VERSION 5.8 ;
BUSBITCHARS "[]" ;
DIVIDERCHAR "/" ;
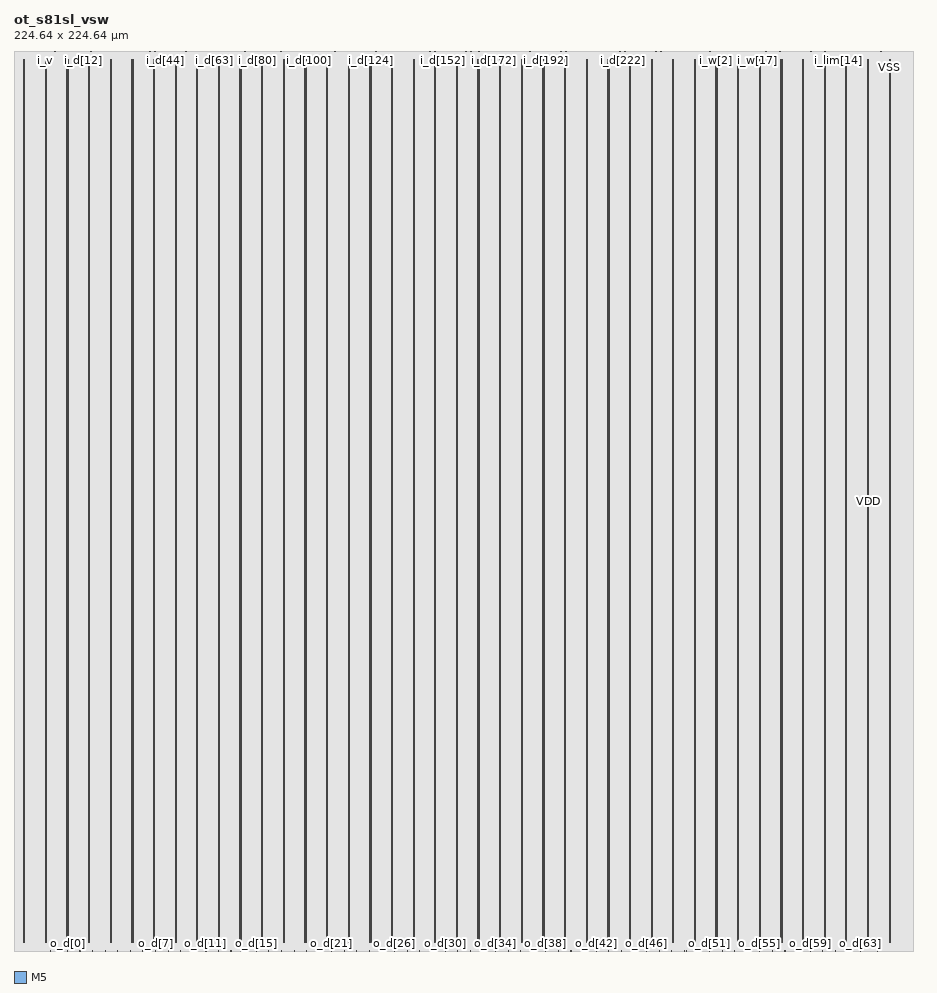
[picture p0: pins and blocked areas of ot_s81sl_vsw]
MACRO ot_s81sl_vsw
  CLASS BLOCK ;
  ORIGIN 0 0 ;
  SIZE 224.640 BY 224.640 ;
  PIN clk
    DIRECTION INPUT ;
    USE SIGNAL ;
    PORT
      LAYER M5 ;
        RECT 56.628000 0.000000 56.676000 0.480000 ;
    END
  END clk
  PIN i_d[0]
    DIRECTION INPUT ;
    USE SIGNAL ;
    PORT
      LAYER M5 ;
        RECT 9.552000 224.556000 9.576000 224.640000 ;
    END
  END i_d[0]
  PIN i_d[100]
    DIRECTION INPUT ;
    USE SIGNAL ;
    PORT
      LAYER M5 ;
        RECT 73.680000 224.556000 73.704000 224.640000 ;
    END
  END i_d[100]
  PIN i_d[101]
    DIRECTION INPUT ;
    USE SIGNAL ;
    PORT
      LAYER M5 ;
        RECT 74.304000 224.556000 74.328000 224.640000 ;
    END
  END i_d[101]
  PIN i_d[102]
    DIRECTION INPUT ;
    USE SIGNAL ;
    PORT
      LAYER M5 ;
        RECT 74.928000 224.556000 74.952000 224.640000 ;
    END
  END i_d[102]
  PIN i_d[103]
    DIRECTION INPUT ;
    USE SIGNAL ;
    PORT
      LAYER M5 ;
        RECT 75.600000 224.556000 75.624000 224.640000 ;
    END
  END i_d[103]
  PIN i_d[104]
    DIRECTION INPUT ;
    USE SIGNAL ;
    PORT
      LAYER M5 ;
        RECT 76.224000 224.556000 76.248000 224.640000 ;
    END
  END i_d[104]
  PIN i_d[105]
    DIRECTION INPUT ;
    USE SIGNAL ;
    PORT
      LAYER M5 ;
        RECT 76.896000 224.556000 76.920000 224.640000 ;
    END
  END i_d[105]
  PIN i_d[106]
    DIRECTION INPUT ;
    USE SIGNAL ;
    PORT
      LAYER M5 ;
        RECT 77.520000 224.556000 77.544000 224.640000 ;
    END
  END i_d[106]
  PIN i_d[107]
    DIRECTION INPUT ;
    USE SIGNAL ;
    PORT
      LAYER M5 ;
        RECT 78.144000 224.556000 78.168000 224.640000 ;
    END
  END i_d[107]
  PIN i_d[108]
    DIRECTION INPUT ;
    USE SIGNAL ;
    PORT
      LAYER M5 ;
        RECT 78.816000 224.556000 78.840000 224.640000 ;
    END
  END i_d[108]
  PIN i_d[109]
    DIRECTION INPUT ;
    USE SIGNAL ;
    PORT
      LAYER M5 ;
        RECT 79.440000 224.556000 79.464000 224.640000 ;
    END
  END i_d[109]
  PIN i_d[10]
    DIRECTION INPUT ;
    USE SIGNAL ;
    PORT
      LAYER M5 ;
        RECT 15.984000 224.556000 16.008000 224.640000 ;
    END
  END i_d[10]
  PIN i_d[110]
    DIRECTION INPUT ;
    USE SIGNAL ;
    PORT
      LAYER M5 ;
        RECT 80.112000 224.556000 80.136000 224.640000 ;
    END
  END i_d[110]
  PIN i_d[111]
    DIRECTION INPUT ;
    USE SIGNAL ;
    PORT
      LAYER M5 ;
        RECT 80.736000 224.556000 80.760000 224.640000 ;
    END
  END i_d[111]
  PIN i_d[112]
    DIRECTION INPUT ;
    USE SIGNAL ;
    PORT
      LAYER M5 ;
        RECT 81.408000 224.556000 81.432000 224.640000 ;
    END
  END i_d[112]
  PIN i_d[113]
    DIRECTION INPUT ;
    USE SIGNAL ;
    PORT
      LAYER M5 ;
        RECT 82.032000 224.556000 82.056000 224.640000 ;
    END
  END i_d[113]
  PIN i_d[114]
    DIRECTION INPUT ;
    USE SIGNAL ;
    PORT
      LAYER M5 ;
        RECT 82.656000 224.556000 82.680000 224.640000 ;
    END
  END i_d[114]
  PIN i_d[115]
    DIRECTION INPUT ;
    USE SIGNAL ;
    PORT
      LAYER M5 ;
        RECT 83.280000 224.556000 83.304000 224.640000 ;
    END
  END i_d[115]
  PIN i_d[116]
    DIRECTION INPUT ;
    USE SIGNAL ;
    PORT
      LAYER M5 ;
        RECT 83.952000 224.556000 83.976000 224.640000 ;
    END
  END i_d[116]
  PIN i_d[117]
    DIRECTION INPUT ;
    USE SIGNAL ;
    PORT
      LAYER M5 ;
        RECT 84.576000 224.556000 84.600000 224.640000 ;
    END
  END i_d[117]
  PIN i_d[118]
    DIRECTION INPUT ;
    USE SIGNAL ;
    PORT
      LAYER M5 ;
        RECT 85.200000 224.556000 85.224000 224.640000 ;
    END
  END i_d[118]
  PIN i_d[119]
    DIRECTION INPUT ;
    USE SIGNAL ;
    PORT
      LAYER M5 ;
        RECT 85.872000 224.556000 85.896000 224.640000 ;
    END
  END i_d[119]
  PIN i_d[11]
    DIRECTION INPUT ;
    USE SIGNAL ;
    PORT
      LAYER M5 ;
        RECT 16.656000 224.556000 16.680000 224.640000 ;
    END
  END i_d[11]
  PIN i_d[120]
    DIRECTION INPUT ;
    USE SIGNAL ;
    PORT
      LAYER M5 ;
        RECT 86.496000 224.556000 86.520000 224.640000 ;
    END
  END i_d[120]
  PIN i_d[121]
    DIRECTION INPUT ;
    USE SIGNAL ;
    PORT
      LAYER M5 ;
        RECT 87.120000 224.556000 87.144000 224.640000 ;
    END
  END i_d[121]
  PIN i_d[122]
    DIRECTION INPUT ;
    USE SIGNAL ;
    PORT
      LAYER M5 ;
        RECT 87.744000 224.556000 87.768000 224.640000 ;
    END
  END i_d[122]
  PIN i_d[123]
    DIRECTION INPUT ;
    USE SIGNAL ;
    PORT
      LAYER M5 ;
        RECT 88.416000 224.556000 88.440000 224.640000 ;
    END
  END i_d[123]
  PIN i_d[124]
    DIRECTION INPUT ;
    USE SIGNAL ;
    PORT
      LAYER M5 ;
        RECT 89.040000 224.556000 89.064000 224.640000 ;
    END
  END i_d[124]
  PIN i_d[125]
    DIRECTION INPUT ;
    USE SIGNAL ;
    PORT
      LAYER M5 ;
        RECT 89.712000 224.556000 89.736000 224.640000 ;
    END
  END i_d[125]
  PIN i_d[126]
    DIRECTION INPUT ;
    USE SIGNAL ;
    PORT
      LAYER M5 ;
        RECT 90.336000 224.556000 90.360000 224.640000 ;
    END
  END i_d[126]
  PIN i_d[127]
    DIRECTION INPUT ;
    USE SIGNAL ;
    PORT
      LAYER M5 ;
        RECT 91.008000 224.556000 91.032000 224.640000 ;
    END
  END i_d[127]
  PIN i_d[128]
    DIRECTION INPUT ;
    USE SIGNAL ;
    PORT
      LAYER M5 ;
        RECT 91.632000 224.556000 91.656000 224.640000 ;
    END
  END i_d[128]
  PIN i_d[129]
    DIRECTION INPUT ;
    USE SIGNAL ;
    PORT
      LAYER M5 ;
        RECT 92.256000 224.556000 92.280000 224.640000 ;
    END
  END i_d[129]
  PIN i_d[12]
    DIRECTION INPUT ;
    USE SIGNAL ;
    PORT
      LAYER M5 ;
        RECT 17.280000 224.556000 17.304000 224.640000 ;
    END
  END i_d[12]
  PIN i_d[130]
    DIRECTION INPUT ;
    USE SIGNAL ;
    PORT
      LAYER M5 ;
        RECT 92.928000 224.556000 92.952000 224.640000 ;
    END
  END i_d[130]
  PIN i_d[131]
    DIRECTION INPUT ;
    USE SIGNAL ;
    PORT
      LAYER M5 ;
        RECT 93.552000 224.556000 93.576000 224.640000 ;
    END
  END i_d[131]
  PIN i_d[132]
    DIRECTION INPUT ;
    USE SIGNAL ;
    PORT
      LAYER M5 ;
        RECT 94.176000 224.556000 94.200000 224.640000 ;
    END
  END i_d[132]
  PIN i_d[133]
    DIRECTION INPUT ;
    USE SIGNAL ;
    PORT
      LAYER M5 ;
        RECT 94.848000 224.556000 94.872000 224.640000 ;
    END
  END i_d[133]
  PIN i_d[134]
    DIRECTION INPUT ;
    USE SIGNAL ;
    PORT
      LAYER M5 ;
        RECT 95.472000 224.556000 95.496000 224.640000 ;
    END
  END i_d[134]
  PIN i_d[135]
    DIRECTION INPUT ;
    USE SIGNAL ;
    PORT
      LAYER M5 ;
        RECT 96.096000 224.556000 96.120000 224.640000 ;
    END
  END i_d[135]
  PIN i_d[136]
    DIRECTION INPUT ;
    USE SIGNAL ;
    PORT
      LAYER M5 ;
        RECT 96.768000 224.556000 96.792000 224.640000 ;
    END
  END i_d[136]
  PIN i_d[137]
    DIRECTION INPUT ;
    USE SIGNAL ;
    PORT
      LAYER M5 ;
        RECT 97.392000 224.556000 97.416000 224.640000 ;
    END
  END i_d[137]
  PIN i_d[138]
    DIRECTION INPUT ;
    USE SIGNAL ;
    PORT
      LAYER M5 ;
        RECT 98.016000 224.556000 98.040000 224.640000 ;
    END
  END i_d[138]
  PIN i_d[139]
    DIRECTION INPUT ;
    USE SIGNAL ;
    PORT
      LAYER M5 ;
        RECT 98.688000 224.556000 98.712000 224.640000 ;
    END
  END i_d[139]
  PIN i_d[13]
    DIRECTION INPUT ;
    USE SIGNAL ;
    PORT
      LAYER M5 ;
        RECT 17.904000 224.556000 17.928000 224.640000 ;
    END
  END i_d[13]
  PIN i_d[140]
    DIRECTION INPUT ;
    USE SIGNAL ;
    PORT
      LAYER M5 ;
        RECT 99.312000 224.556000 99.336000 224.640000 ;
    END
  END i_d[140]
  PIN i_d[141]
    DIRECTION INPUT ;
    USE SIGNAL ;
    PORT
      LAYER M5 ;
        RECT 99.936000 224.556000 99.960000 224.640000 ;
    END
  END i_d[141]
  PIN i_d[142]
    DIRECTION INPUT ;
    USE SIGNAL ;
    PORT
      LAYER M5 ;
        RECT 100.560000 224.556000 100.584000 224.640000 ;
    END
  END i_d[142]
  PIN i_d[143]
    DIRECTION INPUT ;
    USE SIGNAL ;
    PORT
      LAYER M5 ;
        RECT 101.232000 224.556000 101.256000 224.640000 ;
    END
  END i_d[143]
  PIN i_d[144]
    DIRECTION INPUT ;
    USE SIGNAL ;
    PORT
      LAYER M5 ;
        RECT 101.856000 224.556000 101.880000 224.640000 ;
    END
  END i_d[144]
  PIN i_d[145]
    DIRECTION INPUT ;
    USE SIGNAL ;
    PORT
      LAYER M5 ;
        RECT 102.528000 224.556000 102.552000 224.640000 ;
    END
  END i_d[145]
  PIN i_d[146]
    DIRECTION INPUT ;
    USE SIGNAL ;
    PORT
      LAYER M5 ;
        RECT 103.152000 224.556000 103.176000 224.640000 ;
    END
  END i_d[146]
  PIN i_d[147]
    DIRECTION INPUT ;
    USE SIGNAL ;
    PORT
      LAYER M5 ;
        RECT 103.824000 224.556000 103.848000 224.640000 ;
    END
  END i_d[147]
  PIN i_d[148]
    DIRECTION INPUT ;
    USE SIGNAL ;
    PORT
      LAYER M5 ;
        RECT 104.448000 224.556000 104.472000 224.640000 ;
    END
  END i_d[148]
  PIN i_d[149]
    DIRECTION INPUT ;
    USE SIGNAL ;
    PORT
      LAYER M5 ;
        RECT 105.072000 224.556000 105.096000 224.640000 ;
    END
  END i_d[149]
  PIN i_d[14]
    DIRECTION INPUT ;
    USE SIGNAL ;
    PORT
      LAYER M5 ;
        RECT 18.576000 224.556000 18.600000 224.640000 ;
    END
  END i_d[14]
  PIN i_d[150]
    DIRECTION INPUT ;
    USE SIGNAL ;
    PORT
      LAYER M5 ;
        RECT 105.744000 224.556000 105.768000 224.640000 ;
    END
  END i_d[150]
  PIN i_d[151]
    DIRECTION INPUT ;
    USE SIGNAL ;
    PORT
      LAYER M5 ;
        RECT 106.368000 224.556000 106.392000 224.640000 ;
    END
  END i_d[151]
  PIN i_d[152]
    DIRECTION INPUT ;
    USE SIGNAL ;
    PORT
      LAYER M5 ;
        RECT 107.040000 224.556000 107.064000 224.640000 ;
    END
  END i_d[152]
  PIN i_d[153]
    DIRECTION INPUT ;
    USE SIGNAL ;
    PORT
      LAYER M5 ;
        RECT 107.664000 224.556000 107.688000 224.640000 ;
    END
  END i_d[153]
  PIN i_d[154]
    DIRECTION INPUT ;
    USE SIGNAL ;
    PORT
      LAYER M5 ;
        RECT 108.288000 224.556000 108.312000 224.640000 ;
    END
  END i_d[154]
  PIN i_d[155]
    DIRECTION INPUT ;
    USE SIGNAL ;
    PORT
      LAYER M5 ;
        RECT 108.912000 224.556000 108.936000 224.640000 ;
    END
  END i_d[155]
  PIN i_d[156]
    DIRECTION INPUT ;
    USE SIGNAL ;
    PORT
      LAYER M5 ;
        RECT 109.584000 224.556000 109.608000 224.640000 ;
    END
  END i_d[156]
  PIN i_d[157]
    DIRECTION INPUT ;
    USE SIGNAL ;
    PORT
      LAYER M5 ;
        RECT 110.208000 224.556000 110.232000 224.640000 ;
    END
  END i_d[157]
  PIN i_d[158]
    DIRECTION INPUT ;
    USE SIGNAL ;
    PORT
      LAYER M5 ;
        RECT 110.832000 224.556000 110.856000 224.640000 ;
    END
  END i_d[158]
  PIN i_d[159]
    DIRECTION INPUT ;
    USE SIGNAL ;
    PORT
      LAYER M5 ;
        RECT 111.504000 224.556000 111.528000 224.640000 ;
    END
  END i_d[159]
  PIN i_d[15]
    DIRECTION INPUT ;
    USE SIGNAL ;
    PORT
      LAYER M5 ;
        RECT 19.200000 224.556000 19.224000 224.640000 ;
    END
  END i_d[15]
  PIN i_d[160]
    DIRECTION INPUT ;
    USE SIGNAL ;
    PORT
      LAYER M5 ;
        RECT 112.128000 224.556000 112.152000 224.640000 ;
    END
  END i_d[160]
  PIN i_d[161]
    DIRECTION INPUT ;
    USE SIGNAL ;
    PORT
      LAYER M5 ;
        RECT 112.800000 224.556000 112.824000 224.640000 ;
    END
  END i_d[161]
  PIN i_d[162]
    DIRECTION INPUT ;
    USE SIGNAL ;
    PORT
      LAYER M5 ;
        RECT 113.424000 224.556000 113.448000 224.640000 ;
    END
  END i_d[162]
  PIN i_d[163]
    DIRECTION INPUT ;
    USE SIGNAL ;
    PORT
      LAYER M5 ;
        RECT 114.048000 224.556000 114.072000 224.640000 ;
    END
  END i_d[163]
  PIN i_d[164]
    DIRECTION INPUT ;
    USE SIGNAL ;
    PORT
      LAYER M5 ;
        RECT 114.672000 224.556000 114.696000 224.640000 ;
    END
  END i_d[164]
  PIN i_d[165]
    DIRECTION INPUT ;
    USE SIGNAL ;
    PORT
      LAYER M5 ;
        RECT 115.344000 224.556000 115.368000 224.640000 ;
    END
  END i_d[165]
  PIN i_d[166]
    DIRECTION INPUT ;
    USE SIGNAL ;
    PORT
      LAYER M5 ;
        RECT 116.064000 224.556000 116.088000 224.640000 ;
    END
  END i_d[166]
  PIN i_d[167]
    DIRECTION INPUT ;
    USE SIGNAL ;
    PORT
      LAYER M5 ;
        RECT 116.640000 224.556000 116.664000 224.640000 ;
    END
  END i_d[167]
  PIN i_d[168]
    DIRECTION INPUT ;
    USE SIGNAL ;
    PORT
      LAYER M5 ;
        RECT 117.264000 224.556000 117.288000 224.640000 ;
    END
  END i_d[168]
  PIN i_d[169]
    DIRECTION INPUT ;
    USE SIGNAL ;
    PORT
      LAYER M5 ;
        RECT 117.888000 224.556000 117.912000 224.640000 ;
    END
  END i_d[169]
  PIN i_d[16]
    DIRECTION INPUT ;
    USE SIGNAL ;
    PORT
      LAYER M5 ;
        RECT 19.824000 224.556000 19.848000 224.640000 ;
    END
  END i_d[16]
  PIN i_d[170]
    DIRECTION INPUT ;
    USE SIGNAL ;
    PORT
      LAYER M5 ;
        RECT 118.560000 224.556000 118.584000 224.640000 ;
    END
  END i_d[170]
  PIN i_d[171]
    DIRECTION INPUT ;
    USE SIGNAL ;
    PORT
      LAYER M5 ;
        RECT 119.184000 224.556000 119.208000 224.640000 ;
    END
  END i_d[171]
  PIN i_d[172]
    DIRECTION INPUT ;
    USE SIGNAL ;
    PORT
      LAYER M5 ;
        RECT 119.856000 224.556000 119.880000 224.640000 ;
    END
  END i_d[172]
  PIN i_d[173]
    DIRECTION INPUT ;
    USE SIGNAL ;
    PORT
      LAYER M5 ;
        RECT 120.480000 224.556000 120.504000 224.640000 ;
    END
  END i_d[173]
  PIN i_d[174]
    DIRECTION INPUT ;
    USE SIGNAL ;
    PORT
      LAYER M5 ;
        RECT 121.104000 224.556000 121.128000 224.640000 ;
    END
  END i_d[174]
  PIN i_d[175]
    DIRECTION INPUT ;
    USE SIGNAL ;
    PORT
      LAYER M5 ;
        RECT 121.728000 224.556000 121.752000 224.640000 ;
    END
  END i_d[175]
  PIN i_d[176]
    DIRECTION INPUT ;
    USE SIGNAL ;
    PORT
      LAYER M5 ;
        RECT 122.400000 224.556000 122.424000 224.640000 ;
    END
  END i_d[176]
  PIN i_d[177]
    DIRECTION INPUT ;
    USE SIGNAL ;
    PORT
      LAYER M5 ;
        RECT 123.024000 224.556000 123.048000 224.640000 ;
    END
  END i_d[177]
  PIN i_d[178]
    DIRECTION INPUT ;
    USE SIGNAL ;
    PORT
      LAYER M5 ;
        RECT 123.648000 224.556000 123.672000 224.640000 ;
    END
  END i_d[178]
  PIN i_d[179]
    DIRECTION INPUT ;
    USE SIGNAL ;
    PORT
      LAYER M5 ;
        RECT 124.320000 224.556000 124.344000 224.640000 ;
    END
  END i_d[179]
  PIN i_d[17]
    DIRECTION INPUT ;
    USE SIGNAL ;
    PORT
      LAYER M5 ;
        RECT 20.496000 224.556000 20.520000 224.640000 ;
    END
  END i_d[17]
  PIN i_d[180]
    DIRECTION INPUT ;
    USE SIGNAL ;
    PORT
      LAYER M5 ;
        RECT 124.944000 224.556000 124.968000 224.640000 ;
    END
  END i_d[180]
  PIN i_d[181]
    DIRECTION INPUT ;
    USE SIGNAL ;
    PORT
      LAYER M5 ;
        RECT 125.616000 224.556000 125.640000 224.640000 ;
    END
  END i_d[181]
  PIN i_d[182]
    DIRECTION INPUT ;
    USE SIGNAL ;
    PORT
      LAYER M5 ;
        RECT 126.240000 224.556000 126.264000 224.640000 ;
    END
  END i_d[182]
  PIN i_d[183]
    DIRECTION INPUT ;
    USE SIGNAL ;
    PORT
      LAYER M5 ;
        RECT 126.864000 224.556000 126.888000 224.640000 ;
    END
  END i_d[183]
  PIN i_d[184]
    DIRECTION INPUT ;
    USE SIGNAL ;
    PORT
      LAYER M5 ;
        RECT 127.488000 224.556000 127.512000 224.640000 ;
    END
  END i_d[184]
  PIN i_d[185]
    DIRECTION INPUT ;
    USE SIGNAL ;
    PORT
      LAYER M5 ;
        RECT 128.160000 224.556000 128.184000 224.640000 ;
    END
  END i_d[185]
  PIN i_d[186]
    DIRECTION INPUT ;
    USE SIGNAL ;
    PORT
      LAYER M5 ;
        RECT 128.784000 224.556000 128.808000 224.640000 ;
    END
  END i_d[186]
  PIN i_d[187]
    DIRECTION INPUT ;
    USE SIGNAL ;
    PORT
      LAYER M5 ;
        RECT 129.456000 224.556000 129.480000 224.640000 ;
    END
  END i_d[187]
  PIN i_d[188]
    DIRECTION INPUT ;
    USE SIGNAL ;
    PORT
      LAYER M5 ;
        RECT 130.080000 224.556000 130.104000 224.640000 ;
    END
  END i_d[188]
  PIN i_d[189]
    DIRECTION INPUT ;
    USE SIGNAL ;
    PORT
      LAYER M5 ;
        RECT 130.704000 224.556000 130.728000 224.640000 ;
    END
  END i_d[189]
  PIN i_d[18]
    DIRECTION INPUT ;
    USE SIGNAL ;
    PORT
      LAYER M5 ;
        RECT 21.120000 224.556000 21.144000 224.640000 ;
    END
  END i_d[18]
  PIN i_d[190]
    DIRECTION INPUT ;
    USE SIGNAL ;
    PORT
      LAYER M5 ;
        RECT 131.376000 224.556000 131.400000 224.640000 ;
    END
  END i_d[190]
  PIN i_d[191]
    DIRECTION INPUT ;
    USE SIGNAL ;
    PORT
      LAYER M5 ;
        RECT 132.000000 224.556000 132.024000 224.640000 ;
    END
  END i_d[191]
  PIN i_d[192]
    DIRECTION INPUT ;
    USE SIGNAL ;
    PORT
      LAYER M5 ;
        RECT 132.672000 224.556000 132.696000 224.640000 ;
    END
  END i_d[192]
  PIN i_d[193]
    DIRECTION INPUT ;
    USE SIGNAL ;
    PORT
      LAYER M5 ;
        RECT 133.296000 224.556000 133.320000 224.640000 ;
    END
  END i_d[193]
  PIN i_d[194]
    DIRECTION INPUT ;
    USE SIGNAL ;
    PORT
      LAYER M5 ;
        RECT 133.920000 224.556000 133.944000 224.640000 ;
    END
  END i_d[194]
  PIN i_d[195]
    DIRECTION INPUT ;
    USE SIGNAL ;
    PORT
      LAYER M5 ;
        RECT 134.592000 224.556000 134.616000 224.640000 ;
    END
  END i_d[195]
  PIN i_d[196]
    DIRECTION INPUT ;
    USE SIGNAL ;
    PORT
      LAYER M5 ;
        RECT 135.216000 224.556000 135.240000 224.640000 ;
    END
  END i_d[196]
  PIN i_d[197]
    DIRECTION INPUT ;
    USE SIGNAL ;
    PORT
      LAYER M5 ;
        RECT 135.840000 224.556000 135.864000 224.640000 ;
    END
  END i_d[197]
  PIN i_d[198]
    DIRECTION INPUT ;
    USE SIGNAL ;
    PORT
      LAYER M5 ;
        RECT 136.512000 224.556000 136.536000 224.640000 ;
    END
  END i_d[198]
  PIN i_d[199]
    DIRECTION INPUT ;
    USE SIGNAL ;
    PORT
      LAYER M5 ;
        RECT 137.136000 224.556000 137.160000 224.640000 ;
    END
  END i_d[199]
  PIN i_d[19]
    DIRECTION INPUT ;
    USE SIGNAL ;
    PORT
      LAYER M5 ;
        RECT 21.744000 224.556000 21.768000 224.640000 ;
    END
  END i_d[19]
  PIN i_d[1]
    DIRECTION INPUT ;
    USE SIGNAL ;
    PORT
      LAYER M5 ;
        RECT 10.224000 224.556000 10.248000 224.640000 ;
    END
  END i_d[1]
  PIN i_d[200]
    DIRECTION INPUT ;
    USE SIGNAL ;
    PORT
      LAYER M5 ;
        RECT 137.760000 224.556000 137.784000 224.640000 ;
    END
  END i_d[200]
  PIN i_d[201]
    DIRECTION INPUT ;
    USE SIGNAL ;
    PORT
      LAYER M5 ;
        RECT 138.432000 224.556000 138.456000 224.640000 ;
    END
  END i_d[201]
  PIN i_d[202]
    DIRECTION INPUT ;
    USE SIGNAL ;
    PORT
      LAYER M5 ;
        RECT 139.056000 224.556000 139.080000 224.640000 ;
    END
  END i_d[202]
  PIN i_d[203]
    DIRECTION INPUT ;
    USE SIGNAL ;
    PORT
      LAYER M5 ;
        RECT 139.680000 224.556000 139.704000 224.640000 ;
    END
  END i_d[203]
  PIN i_d[204]
    DIRECTION INPUT ;
    USE SIGNAL ;
    PORT
      LAYER M5 ;
        RECT 140.304000 224.556000 140.328000 224.640000 ;
    END
  END i_d[204]
  PIN i_d[205]
    DIRECTION INPUT ;
    USE SIGNAL ;
    PORT
      LAYER M5 ;
        RECT 140.976000 224.556000 141.000000 224.640000 ;
    END
  END i_d[205]
  PIN i_d[206]
    DIRECTION INPUT ;
    USE SIGNAL ;
    PORT
      LAYER M5 ;
        RECT 141.600000 224.556000 141.624000 224.640000 ;
    END
  END i_d[206]
  PIN i_d[207]
    DIRECTION INPUT ;
    USE SIGNAL ;
    PORT
      LAYER M5 ;
        RECT 142.272000 224.556000 142.296000 224.640000 ;
    END
  END i_d[207]
  PIN i_d[208]
    DIRECTION INPUT ;
    USE SIGNAL ;
    PORT
      LAYER M5 ;
        RECT 142.896000 224.556000 142.920000 224.640000 ;
    END
  END i_d[208]
  PIN i_d[209]
    DIRECTION INPUT ;
    USE SIGNAL ;
    PORT
      LAYER M5 ;
        RECT 143.520000 224.556000 143.544000 224.640000 ;
    END
  END i_d[209]
  PIN i_d[20]
    DIRECTION INPUT ;
    USE SIGNAL ;
    PORT
      LAYER M5 ;
        RECT 22.368000 224.556000 22.392000 224.640000 ;
    END
  END i_d[20]
  PIN i_d[210]
    DIRECTION INPUT ;
    USE SIGNAL ;
    PORT
      LAYER M5 ;
        RECT 144.192000 224.556000 144.216000 224.640000 ;
    END
  END i_d[210]
  PIN i_d[211]
    DIRECTION INPUT ;
    USE SIGNAL ;
    PORT
      LAYER M5 ;
        RECT 144.816000 224.556000 144.840000 224.640000 ;
    END
  END i_d[211]
  PIN i_d[212]
    DIRECTION INPUT ;
    USE SIGNAL ;
    PORT
      LAYER M5 ;
        RECT 145.488000 224.556000 145.512000 224.640000 ;
    END
  END i_d[212]
  PIN i_d[213]
    DIRECTION INPUT ;
    USE SIGNAL ;
    PORT
      LAYER M5 ;
        RECT 146.112000 224.556000 146.136000 224.640000 ;
    END
  END i_d[213]
  PIN i_d[214]
    DIRECTION INPUT ;
    USE SIGNAL ;
    PORT
      LAYER M5 ;
        RECT 146.736000 224.556000 146.760000 224.640000 ;
    END
  END i_d[214]
  PIN i_d[215]
    DIRECTION INPUT ;
    USE SIGNAL ;
    PORT
      LAYER M5 ;
        RECT 147.408000 224.556000 147.432000 224.640000 ;
    END
  END i_d[215]
  PIN i_d[216]
    DIRECTION INPUT ;
    USE SIGNAL ;
    PORT
      LAYER M5 ;
        RECT 148.032000 224.556000 148.056000 224.640000 ;
    END
  END i_d[216]
  PIN i_d[217]
    DIRECTION INPUT ;
    USE SIGNAL ;
    PORT
      LAYER M5 ;
        RECT 148.656000 224.556000 148.680000 224.640000 ;
    END
  END i_d[217]
  PIN i_d[218]
    DIRECTION INPUT ;
    USE SIGNAL ;
    PORT
      LAYER M5 ;
        RECT 149.328000 224.556000 149.352000 224.640000 ;
    END
  END i_d[218]
  PIN i_d[219]
    DIRECTION INPUT ;
    USE SIGNAL ;
    PORT
      LAYER M5 ;
        RECT 149.952000 224.556000 149.976000 224.640000 ;
    END
  END i_d[219]
  PIN i_d[21]
    DIRECTION INPUT ;
    USE SIGNAL ;
    PORT
      LAYER M5 ;
        RECT 23.040000 224.556000 23.064000 224.640000 ;
    END
  END i_d[21]
  PIN i_d[220]
    DIRECTION INPUT ;
    USE SIGNAL ;
    PORT
      LAYER M5 ;
        RECT 150.576000 224.556000 150.600000 224.640000 ;
    END
  END i_d[220]
  PIN i_d[221]
    DIRECTION INPUT ;
    USE SIGNAL ;
    PORT
      LAYER M5 ;
        RECT 151.248000 224.556000 151.272000 224.640000 ;
    END
  END i_d[221]
  PIN i_d[222]
    DIRECTION INPUT ;
    USE SIGNAL ;
    PORT
      LAYER M5 ;
        RECT 151.872000 224.556000 151.896000 224.640000 ;
    END
  END i_d[222]
  PIN i_d[223]
    DIRECTION INPUT ;
    USE SIGNAL ;
    PORT
      LAYER M5 ;
        RECT 152.496000 224.556000 152.520000 224.640000 ;
    END
  END i_d[223]
  PIN i_d[224]
    DIRECTION INPUT ;
    USE SIGNAL ;
    PORT
      LAYER M5 ;
        RECT 153.120000 224.556000 153.144000 224.640000 ;
    END
  END i_d[224]
  PIN i_d[225]
    DIRECTION INPUT ;
    USE SIGNAL ;
    PORT
      LAYER M5 ;
        RECT 153.792000 224.556000 153.816000 224.640000 ;
    END
  END i_d[225]
  PIN i_d[226]
    DIRECTION INPUT ;
    USE SIGNAL ;
    PORT
      LAYER M5 ;
        RECT 154.416000 224.556000 154.440000 224.640000 ;
    END
  END i_d[226]
  PIN i_d[227]
    DIRECTION INPUT ;
    USE SIGNAL ;
    PORT
      LAYER M5 ;
        RECT 155.088000 224.556000 155.112000 224.640000 ;
    END
  END i_d[227]
  PIN i_d[228]
    DIRECTION INPUT ;
    USE SIGNAL ;
    PORT
      LAYER M5 ;
        RECT 155.712000 224.556000 155.736000 224.640000 ;
    END
  END i_d[228]
  PIN i_d[229]
    DIRECTION INPUT ;
    USE SIGNAL ;
    PORT
      LAYER M5 ;
        RECT 156.384000 224.556000 156.408000 224.640000 ;
    END
  END i_d[229]
  PIN i_d[22]
    DIRECTION INPUT ;
    USE SIGNAL ;
    PORT
      LAYER M5 ;
        RECT 23.664000 224.556000 23.688000 224.640000 ;
    END
  END i_d[22]
  PIN i_d[230]
    DIRECTION INPUT ;
    USE SIGNAL ;
    PORT
      LAYER M5 ;
        RECT 157.008000 224.556000 157.032000 224.640000 ;
    END
  END i_d[230]
  PIN i_d[231]
    DIRECTION INPUT ;
    USE SIGNAL ;
    PORT
      LAYER M5 ;
        RECT 157.632000 224.556000 157.656000 224.640000 ;
    END
  END i_d[231]
  PIN i_d[232]
    DIRECTION INPUT ;
    USE SIGNAL ;
    PORT
      LAYER M5 ;
        RECT 158.304000 224.556000 158.328000 224.640000 ;
    END
  END i_d[232]
  PIN i_d[233]
    DIRECTION INPUT ;
    USE SIGNAL ;
    PORT
      LAYER M5 ;
        RECT 158.928000 224.556000 158.952000 224.640000 ;
    END
  END i_d[233]
  PIN i_d[234]
    DIRECTION INPUT ;
    USE SIGNAL ;
    PORT
      LAYER M5 ;
        RECT 159.552000 224.556000 159.576000 224.640000 ;
    END
  END i_d[234]
  PIN i_d[235]
    DIRECTION INPUT ;
    USE SIGNAL ;
    PORT
      LAYER M5 ;
        RECT 160.224000 224.556000 160.248000 224.640000 ;
    END
  END i_d[235]
  PIN i_d[236]
    DIRECTION INPUT ;
    USE SIGNAL ;
    PORT
      LAYER M5 ;
        RECT 160.848000 224.556000 160.872000 224.640000 ;
    END
  END i_d[236]
  PIN i_d[237]
    DIRECTION INPUT ;
    USE SIGNAL ;
    PORT
      LAYER M5 ;
        RECT 161.472000 224.556000 161.496000 224.640000 ;
    END
  END i_d[237]
  PIN i_d[238]
    DIRECTION INPUT ;
    USE SIGNAL ;
    PORT
      LAYER M5 ;
        RECT 162.144000 224.556000 162.168000 224.640000 ;
    END
  END i_d[238]
  PIN i_d[239]
    DIRECTION INPUT ;
    USE SIGNAL ;
    PORT
      LAYER M5 ;
        RECT 162.768000 224.556000 162.792000 224.640000 ;
    END
  END i_d[239]
  PIN i_d[23]
    DIRECTION INPUT ;
    USE SIGNAL ;
    PORT
      LAYER M5 ;
        RECT 24.336000 224.556000 24.360000 224.640000 ;
    END
  END i_d[23]
  PIN i_d[240]
    DIRECTION INPUT ;
    USE SIGNAL ;
    PORT
      LAYER M5 ;
        RECT 163.392000 224.556000 163.416000 224.640000 ;
    END
  END i_d[240]
  PIN i_d[241]
    DIRECTION INPUT ;
    USE SIGNAL ;
    PORT
      LAYER M5 ;
        RECT 164.064000 224.556000 164.088000 224.640000 ;
    END
  END i_d[241]
  PIN i_d[242]
    DIRECTION INPUT ;
    USE SIGNAL ;
    PORT
      LAYER M5 ;
        RECT 164.688000 224.556000 164.712000 224.640000 ;
    END
  END i_d[242]
  PIN i_d[243]
    DIRECTION INPUT ;
    USE SIGNAL ;
    PORT
      LAYER M5 ;
        RECT 165.312000 224.556000 165.336000 224.640000 ;
    END
  END i_d[243]
  PIN i_d[244]
    DIRECTION INPUT ;
    USE SIGNAL ;
    PORT
      LAYER M5 ;
        RECT 165.984000 224.556000 166.008000 224.640000 ;
    END
  END i_d[244]
  PIN i_d[245]
    DIRECTION INPUT ;
    USE SIGNAL ;
    PORT
      LAYER M5 ;
        RECT 166.608000 224.556000 166.632000 224.640000 ;
    END
  END i_d[245]
  PIN i_d[246]
    DIRECTION INPUT ;
    USE SIGNAL ;
    PORT
      LAYER M5 ;
        RECT 167.232000 224.556000 167.256000 224.640000 ;
    END
  END i_d[246]
  PIN i_d[247]
    DIRECTION INPUT ;
    USE SIGNAL ;
    PORT
      LAYER M5 ;
        RECT 167.904000 224.556000 167.928000 224.640000 ;
    END
  END i_d[247]
  PIN i_d[248]
    DIRECTION INPUT ;
    USE SIGNAL ;
    PORT
      LAYER M5 ;
        RECT 168.528000 224.556000 168.552000 224.640000 ;
    END
  END i_d[248]
  PIN i_d[249]
    DIRECTION INPUT ;
    USE SIGNAL ;
    PORT
      LAYER M5 ;
        RECT 169.200000 224.556000 169.224000 224.640000 ;
    END
  END i_d[249]
  PIN i_d[24]
    DIRECTION INPUT ;
    USE SIGNAL ;
    PORT
      LAYER M5 ;
        RECT 24.960000 224.556000 24.984000 224.640000 ;
    END
  END i_d[24]
  PIN i_d[250]
    DIRECTION INPUT ;
    USE SIGNAL ;
    PORT
      LAYER M5 ;
        RECT 169.824000 224.556000 169.848000 224.640000 ;
    END
  END i_d[250]
  PIN i_d[251]
    DIRECTION INPUT ;
    USE SIGNAL ;
    PORT
      LAYER M5 ;
        RECT 170.448000 224.556000 170.472000 224.640000 ;
    END
  END i_d[251]
  PIN i_d[252]
    DIRECTION INPUT ;
    USE SIGNAL ;
    PORT
      LAYER M5 ;
        RECT 171.120000 224.556000 171.144000 224.640000 ;
    END
  END i_d[252]
  PIN i_d[253]
    DIRECTION INPUT ;
    USE SIGNAL ;
    PORT
      LAYER M5 ;
        RECT 171.744000 224.556000 171.768000 224.640000 ;
    END
  END i_d[253]
  PIN i_d[254]
    DIRECTION INPUT ;
    USE SIGNAL ;
    PORT
      LAYER M5 ;
        RECT 172.416000 224.556000 172.440000 224.640000 ;
    END
  END i_d[254]
  PIN i_d[255]
    DIRECTION INPUT ;
    USE SIGNAL ;
    PORT
      LAYER M5 ;
        RECT 173.040000 224.556000 173.064000 224.640000 ;
    END
  END i_d[255]
  PIN i_d[25]
    DIRECTION INPUT ;
    USE SIGNAL ;
    PORT
      LAYER M5 ;
        RECT 25.584000 224.556000 25.608000 224.640000 ;
    END
  END i_d[25]
  PIN i_d[26]
    DIRECTION INPUT ;
    USE SIGNAL ;
    PORT
      LAYER M5 ;
        RECT 26.256000 224.556000 26.280000 224.640000 ;
    END
  END i_d[26]
  PIN i_d[27]
    DIRECTION INPUT ;
    USE SIGNAL ;
    PORT
      LAYER M5 ;
        RECT 26.880000 224.556000 26.904000 224.640000 ;
    END
  END i_d[27]
  PIN i_d[28]
    DIRECTION INPUT ;
    USE SIGNAL ;
    PORT
      LAYER M5 ;
        RECT 27.552000 224.556000 27.576000 224.640000 ;
    END
  END i_d[28]
  PIN i_d[29]
    DIRECTION INPUT ;
    USE SIGNAL ;
    PORT
      LAYER M5 ;
        RECT 28.176000 224.556000 28.200000 224.640000 ;
    END
  END i_d[29]
  PIN i_d[2]
    DIRECTION INPUT ;
    USE SIGNAL ;
    PORT
      LAYER M5 ;
        RECT 10.848000 224.556000 10.872000 224.640000 ;
    END
  END i_d[2]
  PIN i_d[30]
    DIRECTION INPUT ;
    USE SIGNAL ;
    PORT
      LAYER M5 ;
        RECT 28.800000 224.556000 28.824000 224.640000 ;
    END
  END i_d[30]
  PIN i_d[31]
    DIRECTION INPUT ;
    USE SIGNAL ;
    PORT
      LAYER M5 ;
        RECT 29.472000 224.556000 29.496000 224.640000 ;
    END
  END i_d[31]
  PIN i_d[32]
    DIRECTION INPUT ;
    USE SIGNAL ;
    PORT
      LAYER M5 ;
        RECT 30.096000 224.556000 30.120000 224.640000 ;
    END
  END i_d[32]
  PIN i_d[33]
    DIRECTION INPUT ;
    USE SIGNAL ;
    PORT
      LAYER M5 ;
        RECT 30.720000 224.556000 30.744000 224.640000 ;
    END
  END i_d[33]
  PIN i_d[34]
    DIRECTION INPUT ;
    USE SIGNAL ;
    PORT
      LAYER M5 ;
        RECT 31.392000 224.556000 31.416000 224.640000 ;
    END
  END i_d[34]
  PIN i_d[35]
    DIRECTION INPUT ;
    USE SIGNAL ;
    PORT
      LAYER M5 ;
        RECT 32.016000 224.556000 32.040000 224.640000 ;
    END
  END i_d[35]
  PIN i_d[36]
    DIRECTION INPUT ;
    USE SIGNAL ;
    PORT
      LAYER M5 ;
        RECT 32.640000 224.556000 32.664000 224.640000 ;
    END
  END i_d[36]
  PIN i_d[37]
    DIRECTION INPUT ;
    USE SIGNAL ;
    PORT
      LAYER M5 ;
        RECT 33.312000 224.556000 33.336000 224.640000 ;
    END
  END i_d[37]
  PIN i_d[38]
    DIRECTION INPUT ;
    USE SIGNAL ;
    PORT
      LAYER M5 ;
        RECT 33.936000 224.556000 33.960000 224.640000 ;
    END
  END i_d[38]
  PIN i_d[39]
    DIRECTION INPUT ;
    USE SIGNAL ;
    PORT
      LAYER M5 ;
        RECT 34.560000 224.556000 34.584000 224.640000 ;
    END
  END i_d[39]
  PIN i_d[3]
    DIRECTION INPUT ;
    USE SIGNAL ;
    PORT
      LAYER M5 ;
        RECT 11.520000 224.556000 11.544000 224.640000 ;
    END
  END i_d[3]
  PIN i_d[40]
    DIRECTION INPUT ;
    USE SIGNAL ;
    PORT
      LAYER M5 ;
        RECT 35.184000 224.556000 35.208000 224.640000 ;
    END
  END i_d[40]
  PIN i_d[41]
    DIRECTION INPUT ;
    USE SIGNAL ;
    PORT
      LAYER M5 ;
        RECT 35.856000 224.556000 35.880000 224.640000 ;
    END
  END i_d[41]
  PIN i_d[42]
    DIRECTION INPUT ;
    USE SIGNAL ;
    PORT
      LAYER M5 ;
        RECT 36.480000 224.556000 36.504000 224.640000 ;
    END
  END i_d[42]
  PIN i_d[43]
    DIRECTION INPUT ;
    USE SIGNAL ;
    PORT
      LAYER M5 ;
        RECT 37.152000 224.556000 37.176000 224.640000 ;
    END
  END i_d[43]
  PIN i_d[44]
    DIRECTION INPUT ;
    USE SIGNAL ;
    PORT
      LAYER M5 ;
        RECT 37.776000 224.556000 37.800000 224.640000 ;
    END
  END i_d[44]
  PIN i_d[45]
    DIRECTION INPUT ;
    USE SIGNAL ;
    PORT
      LAYER M5 ;
        RECT 38.448000 224.556000 38.472000 224.640000 ;
    END
  END i_d[45]
  PIN i_d[46]
    DIRECTION INPUT ;
    USE SIGNAL ;
    PORT
      LAYER M5 ;
        RECT 39.072000 224.556000 39.096000 224.640000 ;
    END
  END i_d[46]
  PIN i_d[47]
    DIRECTION INPUT ;
    USE SIGNAL ;
    PORT
      LAYER M5 ;
        RECT 39.696000 224.556000 39.720000 224.640000 ;
    END
  END i_d[47]
  PIN i_d[48]
    DIRECTION INPUT ;
    USE SIGNAL ;
    PORT
      LAYER M5 ;
        RECT 40.368000 224.556000 40.392000 224.640000 ;
    END
  END i_d[48]
  PIN i_d[49]
    DIRECTION INPUT ;
    USE SIGNAL ;
    PORT
      LAYER M5 ;
        RECT 40.992000 224.556000 41.016000 224.640000 ;
    END
  END i_d[49]
  PIN i_d[4]
    DIRECTION INPUT ;
    USE SIGNAL ;
    PORT
      LAYER M5 ;
        RECT 12.144000 224.556000 12.168000 224.640000 ;
    END
  END i_d[4]
  PIN i_d[50]
    DIRECTION INPUT ;
    USE SIGNAL ;
    PORT
      LAYER M5 ;
        RECT 41.616000 224.556000 41.640000 224.640000 ;
    END
  END i_d[50]
  PIN i_d[51]
    DIRECTION INPUT ;
    USE SIGNAL ;
    PORT
      LAYER M5 ;
        RECT 42.288000 224.556000 42.312000 224.640000 ;
    END
  END i_d[51]
  PIN i_d[52]
    DIRECTION INPUT ;
    USE SIGNAL ;
    PORT
      LAYER M5 ;
        RECT 42.912000 224.556000 42.936000 224.640000 ;
    END
  END i_d[52]
  PIN i_d[53]
    DIRECTION INPUT ;
    USE SIGNAL ;
    PORT
      LAYER M5 ;
        RECT 43.536000 224.556000 43.560000 224.640000 ;
    END
  END i_d[53]
  PIN i_d[54]
    DIRECTION INPUT ;
    USE SIGNAL ;
    PORT
      LAYER M5 ;
        RECT 44.208000 224.556000 44.232000 224.640000 ;
    END
  END i_d[54]
  PIN i_d[55]
    DIRECTION INPUT ;
    USE SIGNAL ;
    PORT
      LAYER M5 ;
        RECT 44.832000 224.556000 44.856000 224.640000 ;
    END
  END i_d[55]
  PIN i_d[56]
    DIRECTION INPUT ;
    USE SIGNAL ;
    PORT
      LAYER M5 ;
        RECT 45.456000 224.556000 45.480000 224.640000 ;
    END
  END i_d[56]
  PIN i_d[57]
    DIRECTION INPUT ;
    USE SIGNAL ;
    PORT
      LAYER M5 ;
        RECT 46.128000 224.556000 46.152000 224.640000 ;
    END
  END i_d[57]
  PIN i_d[58]
    DIRECTION INPUT ;
    USE SIGNAL ;
    PORT
      LAYER M5 ;
        RECT 46.752000 224.556000 46.776000 224.640000 ;
    END
  END i_d[58]
  PIN i_d[59]
    DIRECTION INPUT ;
    USE SIGNAL ;
    PORT
      LAYER M5 ;
        RECT 47.376000 224.556000 47.400000 224.640000 ;
    END
  END i_d[59]
  PIN i_d[5]
    DIRECTION INPUT ;
    USE SIGNAL ;
    PORT
      LAYER M5 ;
        RECT 12.768000 224.556000 12.792000 224.640000 ;
    END
  END i_d[5]
  PIN i_d[60]
    DIRECTION INPUT ;
    USE SIGNAL ;
    PORT
      LAYER M5 ;
        RECT 48.048000 224.556000 48.072000 224.640000 ;
    END
  END i_d[60]
  PIN i_d[61]
    DIRECTION INPUT ;
    USE SIGNAL ;
    PORT
      LAYER M5 ;
        RECT 48.672000 224.556000 48.696000 224.640000 ;
    END
  END i_d[61]
  PIN i_d[62]
    DIRECTION INPUT ;
    USE SIGNAL ;
    PORT
      LAYER M5 ;
        RECT 49.296000 224.556000 49.320000 224.640000 ;
    END
  END i_d[62]
  PIN i_d[63]
    DIRECTION INPUT ;
    USE SIGNAL ;
    PORT
      LAYER M5 ;
        RECT 49.968000 224.556000 49.992000 224.640000 ;
    END
  END i_d[63]
  PIN i_d[64]
    DIRECTION INPUT ;
    USE SIGNAL ;
    PORT
      LAYER M5 ;
        RECT 50.592000 224.556000 50.616000 224.640000 ;
    END
  END i_d[64]
  PIN i_d[65]
    DIRECTION INPUT ;
    USE SIGNAL ;
    PORT
      LAYER M5 ;
        RECT 51.264000 224.556000 51.288000 224.640000 ;
    END
  END i_d[65]
  PIN i_d[66]
    DIRECTION INPUT ;
    USE SIGNAL ;
    PORT
      LAYER M5 ;
        RECT 51.888000 224.556000 51.912000 224.640000 ;
    END
  END i_d[66]
  PIN i_d[67]
    DIRECTION INPUT ;
    USE SIGNAL ;
    PORT
      LAYER M5 ;
        RECT 52.512000 224.556000 52.536000 224.640000 ;
    END
  END i_d[67]
  PIN i_d[68]
    DIRECTION INPUT ;
    USE SIGNAL ;
    PORT
      LAYER M5 ;
        RECT 53.184000 224.556000 53.208000 224.640000 ;
    END
  END i_d[68]
  PIN i_d[69]
    DIRECTION INPUT ;
    USE SIGNAL ;
    PORT
      LAYER M5 ;
        RECT 53.808000 224.556000 53.832000 224.640000 ;
    END
  END i_d[69]
  PIN i_d[6]
    DIRECTION INPUT ;
    USE SIGNAL ;
    PORT
      LAYER M5 ;
        RECT 13.440000 224.556000 13.464000 224.640000 ;
    END
  END i_d[6]
  PIN i_d[70]
    DIRECTION INPUT ;
    USE SIGNAL ;
    PORT
      LAYER M5 ;
        RECT 54.480000 224.556000 54.504000 224.640000 ;
    END
  END i_d[70]
  PIN i_d[71]
    DIRECTION INPUT ;
    USE SIGNAL ;
    PORT
      LAYER M5 ;
        RECT 55.104000 224.556000 55.128000 224.640000 ;
    END
  END i_d[71]
  PIN i_d[72]
    DIRECTION INPUT ;
    USE SIGNAL ;
    PORT
      LAYER M5 ;
        RECT 55.728000 224.556000 55.752000 224.640000 ;
    END
  END i_d[72]
  PIN i_d[73]
    DIRECTION INPUT ;
    USE SIGNAL ;
    PORT
      LAYER M5 ;
        RECT 56.352000 224.556000 56.376000 224.640000 ;
    END
  END i_d[73]
  PIN i_d[74]
    DIRECTION INPUT ;
    USE SIGNAL ;
    PORT
      LAYER M5 ;
        RECT 57.024000 224.556000 57.048000 224.640000 ;
    END
  END i_d[74]
  PIN i_d[75]
    DIRECTION INPUT ;
    USE SIGNAL ;
    PORT
      LAYER M5 ;
        RECT 57.648000 224.556000 57.672000 224.640000 ;
    END
  END i_d[75]
  PIN i_d[76]
    DIRECTION INPUT ;
    USE SIGNAL ;
    PORT
      LAYER M5 ;
        RECT 58.272000 224.556000 58.296000 224.640000 ;
    END
  END i_d[76]
  PIN i_d[77]
    DIRECTION INPUT ;
    USE SIGNAL ;
    PORT
      LAYER M5 ;
        RECT 58.944000 224.556000 58.968000 224.640000 ;
    END
  END i_d[77]
  PIN i_d[78]
    DIRECTION INPUT ;
    USE SIGNAL ;
    PORT
      LAYER M5 ;
        RECT 59.568000 224.556000 59.592000 224.640000 ;
    END
  END i_d[78]
  PIN i_d[79]
    DIRECTION INPUT ;
    USE SIGNAL ;
    PORT
      LAYER M5 ;
        RECT 60.240000 224.556000 60.264000 224.640000 ;
    END
  END i_d[79]
  PIN i_d[7]
    DIRECTION INPUT ;
    USE SIGNAL ;
    PORT
      LAYER M5 ;
        RECT 14.064000 224.556000 14.088000 224.640000 ;
    END
  END i_d[7]
  PIN i_d[80]
    DIRECTION INPUT ;
    USE SIGNAL ;
    PORT
      LAYER M5 ;
        RECT 60.864000 224.556000 60.888000 224.640000 ;
    END
  END i_d[80]
  PIN i_d[81]
    DIRECTION INPUT ;
    USE SIGNAL ;
    PORT
      LAYER M5 ;
        RECT 61.488000 224.556000 61.512000 224.640000 ;
    END
  END i_d[81]
  PIN i_d[82]
    DIRECTION INPUT ;
    USE SIGNAL ;
    PORT
      LAYER M5 ;
        RECT 62.112000 224.556000 62.136000 224.640000 ;
    END
  END i_d[82]
  PIN i_d[83]
    DIRECTION INPUT ;
    USE SIGNAL ;
    PORT
      LAYER M5 ;
        RECT 62.784000 224.556000 62.808000 224.640000 ;
    END
  END i_d[83]
  PIN i_d[84]
    DIRECTION INPUT ;
    USE SIGNAL ;
    PORT
      LAYER M5 ;
        RECT 63.408000 224.556000 63.432000 224.640000 ;
    END
  END i_d[84]
  PIN i_d[85]
    DIRECTION INPUT ;
    USE SIGNAL ;
    PORT
      LAYER M5 ;
        RECT 64.080000 224.556000 64.104000 224.640000 ;
    END
  END i_d[85]
  PIN i_d[86]
    DIRECTION INPUT ;
    USE SIGNAL ;
    PORT
      LAYER M5 ;
        RECT 64.704000 224.556000 64.728000 224.640000 ;
    END
  END i_d[86]
  PIN i_d[87]
    DIRECTION INPUT ;
    USE SIGNAL ;
    PORT
      LAYER M5 ;
        RECT 65.328000 224.556000 65.352000 224.640000 ;
    END
  END i_d[87]
  PIN i_d[88]
    DIRECTION INPUT ;
    USE SIGNAL ;
    PORT
      LAYER M5 ;
        RECT 66.000000 224.556000 66.024000 224.640000 ;
    END
  END i_d[88]
  PIN i_d[89]
    DIRECTION INPUT ;
    USE SIGNAL ;
    PORT
      LAYER M5 ;
        RECT 66.624000 224.556000 66.648000 224.640000 ;
    END
  END i_d[89]
  PIN i_d[8]
    DIRECTION INPUT ;
    USE SIGNAL ;
    PORT
      LAYER M5 ;
        RECT 14.736000 224.556000 14.760000 224.640000 ;
    END
  END i_d[8]
  PIN i_d[90]
    DIRECTION INPUT ;
    USE SIGNAL ;
    PORT
      LAYER M5 ;
        RECT 67.296000 224.556000 67.320000 224.640000 ;
    END
  END i_d[90]
  PIN i_d[91]
    DIRECTION INPUT ;
    USE SIGNAL ;
    PORT
      LAYER M5 ;
        RECT 67.920000 224.556000 67.944000 224.640000 ;
    END
  END i_d[91]
  PIN i_d[92]
    DIRECTION INPUT ;
    USE SIGNAL ;
    PORT
      LAYER M5 ;
        RECT 68.544000 224.556000 68.568000 224.640000 ;
    END
  END i_d[92]
  PIN i_d[93]
    DIRECTION INPUT ;
    USE SIGNAL ;
    PORT
      LAYER M5 ;
        RECT 69.168000 224.556000 69.192000 224.640000 ;
    END
  END i_d[93]
  PIN i_d[94]
    DIRECTION INPUT ;
    USE SIGNAL ;
    PORT
      LAYER M5 ;
        RECT 69.840000 224.556000 69.864000 224.640000 ;
    END
  END i_d[94]
  PIN i_d[95]
    DIRECTION INPUT ;
    USE SIGNAL ;
    PORT
      LAYER M5 ;
        RECT 70.464000 224.556000 70.488000 224.640000 ;
    END
  END i_d[95]
  PIN i_d[96]
    DIRECTION INPUT ;
    USE SIGNAL ;
    PORT
      LAYER M5 ;
        RECT 71.088000 224.556000 71.112000 224.640000 ;
    END
  END i_d[96]
  PIN i_d[97]
    DIRECTION INPUT ;
    USE SIGNAL ;
    PORT
      LAYER M5 ;
        RECT 71.760000 224.556000 71.784000 224.640000 ;
    END
  END i_d[97]
  PIN i_d[98]
    DIRECTION INPUT ;
    USE SIGNAL ;
    PORT
      LAYER M5 ;
        RECT 72.384000 224.556000 72.408000 224.640000 ;
    END
  END i_d[98]
  PIN i_d[99]
    DIRECTION INPUT ;
    USE SIGNAL ;
    PORT
      LAYER M5 ;
        RECT 73.056000 224.556000 73.080000 224.640000 ;
    END
  END i_d[99]
  PIN i_d[9]
    DIRECTION INPUT ;
    USE SIGNAL ;
    PORT
      LAYER M5 ;
        RECT 15.360000 224.556000 15.384000 224.640000 ;
    END
  END i_d[9]
  PIN i_lim[0]
    DIRECTION INPUT ;
    USE SIGNAL ;
    PORT
      LAYER M5 ;
        RECT 196.080000 224.556000 196.104000 224.640000 ;
    END
  END i_lim[0]
  PIN i_lim[10]
    DIRECTION INPUT ;
    USE SIGNAL ;
    PORT
      LAYER M5 ;
        RECT 203.088000 224.556000 203.112000 224.640000 ;
    END
  END i_lim[10]
  PIN i_lim[11]
    DIRECTION INPUT ;
    USE SIGNAL ;
    PORT
      LAYER M5 ;
        RECT 203.808000 224.556000 203.832000 224.640000 ;
    END
  END i_lim[11]
  PIN i_lim[12]
    DIRECTION INPUT ;
    USE SIGNAL ;
    PORT
      LAYER M5 ;
        RECT 204.528000 224.556000 204.552000 224.640000 ;
    END
  END i_lim[12]
  PIN i_lim[13]
    DIRECTION INPUT ;
    USE SIGNAL ;
    PORT
      LAYER M5 ;
        RECT 205.200000 224.556000 205.224000 224.640000 ;
    END
  END i_lim[13]
  PIN i_lim[14]
    DIRECTION INPUT ;
    USE SIGNAL ;
    PORT
      LAYER M5 ;
        RECT 205.872000 224.556000 205.896000 224.640000 ;
    END
  END i_lim[14]
  PIN i_lim[15]
    DIRECTION INPUT ;
    USE SIGNAL ;
    PORT
      LAYER M5 ;
        RECT 206.592000 224.556000 206.616000 224.640000 ;
    END
  END i_lim[15]
  PIN i_lim[16]
    DIRECTION INPUT ;
    USE SIGNAL ;
    PORT
      LAYER M5 ;
        RECT 207.264000 224.556000 207.288000 224.640000 ;
    END
  END i_lim[16]
  PIN i_lim[17]
    DIRECTION INPUT ;
    USE SIGNAL ;
    PORT
      LAYER M5 ;
        RECT 207.984000 224.556000 208.008000 224.640000 ;
    END
  END i_lim[17]
  PIN i_lim[18]
    DIRECTION INPUT ;
    USE SIGNAL ;
    PORT
      LAYER M5 ;
        RECT 208.704000 224.556000 208.728000 224.640000 ;
    END
  END i_lim[18]
  PIN i_lim[19]
    DIRECTION INPUT ;
    USE SIGNAL ;
    PORT
      LAYER M5 ;
        RECT 209.376000 224.556000 209.400000 224.640000 ;
    END
  END i_lim[19]
  PIN i_lim[1]
    DIRECTION INPUT ;
    USE SIGNAL ;
    PORT
      LAYER M5 ;
        RECT 196.800000 224.556000 196.824000 224.640000 ;
    END
  END i_lim[1]
  PIN i_lim[20]
    DIRECTION INPUT ;
    USE SIGNAL ;
    PORT
      LAYER M5 ;
        RECT 210.096000 224.556000 210.120000 224.640000 ;
    END
  END i_lim[20]
  PIN i_lim[21]
    DIRECTION INPUT ;
    USE SIGNAL ;
    PORT
      LAYER M5 ;
        RECT 210.816000 224.556000 210.840000 224.640000 ;
    END
  END i_lim[21]
  PIN i_lim[22]
    DIRECTION INPUT ;
    USE SIGNAL ;
    PORT
      LAYER M5 ;
        RECT 211.488000 224.556000 211.512000 224.640000 ;
    END
  END i_lim[22]
  PIN i_lim[23]
    DIRECTION INPUT ;
    USE SIGNAL ;
    PORT
      LAYER M5 ;
        RECT 212.208000 224.556000 212.232000 224.640000 ;
    END
  END i_lim[23]
  PIN i_lim[24]
    DIRECTION INPUT ;
    USE SIGNAL ;
    PORT
      LAYER M5 ;
        RECT 212.880000 224.556000 212.904000 224.640000 ;
    END
  END i_lim[24]
  PIN i_lim[25]
    DIRECTION INPUT ;
    USE SIGNAL ;
    PORT
      LAYER M5 ;
        RECT 213.600000 224.556000 213.624000 224.640000 ;
    END
  END i_lim[25]
  PIN i_lim[26]
    DIRECTION INPUT ;
    USE SIGNAL ;
    PORT
      LAYER M5 ;
        RECT 214.320000 224.556000 214.344000 224.640000 ;
    END
  END i_lim[26]
  PIN i_lim[27]
    DIRECTION INPUT ;
    USE SIGNAL ;
    PORT
      LAYER M5 ;
        RECT 214.992000 224.556000 215.016000 224.640000 ;
    END
  END i_lim[27]
  PIN i_lim[28]
    DIRECTION INPUT ;
    USE SIGNAL ;
    PORT
      LAYER M5 ;
        RECT 215.712000 224.556000 215.736000 224.640000 ;
    END
  END i_lim[28]
  PIN i_lim[29]
    DIRECTION INPUT ;
    USE SIGNAL ;
    PORT
      LAYER M5 ;
        RECT 216.384000 224.556000 216.408000 224.640000 ;
    END
  END i_lim[29]
  PIN i_lim[2]
    DIRECTION INPUT ;
    USE SIGNAL ;
    PORT
      LAYER M5 ;
        RECT 197.472000 224.556000 197.496000 224.640000 ;
    END
  END i_lim[2]
  PIN i_lim[30]
    DIRECTION INPUT ;
    USE SIGNAL ;
    PORT
      LAYER M5 ;
        RECT 217.104000 224.556000 217.128000 224.640000 ;
    END
  END i_lim[30]
  PIN i_lim[31]
    DIRECTION INPUT ;
    USE SIGNAL ;
    PORT
      LAYER M5 ;
        RECT 217.776000 224.556000 217.800000 224.640000 ;
    END
  END i_lim[31]
  PIN i_lim[3]
    DIRECTION INPUT ;
    USE SIGNAL ;
    PORT
      LAYER M5 ;
        RECT 198.192000 224.556000 198.216000 224.640000 ;
    END
  END i_lim[3]
  PIN i_lim[4]
    DIRECTION INPUT ;
    USE SIGNAL ;
    PORT
      LAYER M5 ;
        RECT 198.912000 224.556000 198.936000 224.640000 ;
    END
  END i_lim[4]
  PIN i_lim[5]
    DIRECTION INPUT ;
    USE SIGNAL ;
    PORT
      LAYER M5 ;
        RECT 199.584000 224.556000 199.608000 224.640000 ;
    END
  END i_lim[5]
  PIN i_lim[6]
    DIRECTION INPUT ;
    USE SIGNAL ;
    PORT
      LAYER M5 ;
        RECT 200.304000 224.556000 200.328000 224.640000 ;
    END
  END i_lim[6]
  PIN i_lim[7]
    DIRECTION INPUT ;
    USE SIGNAL ;
    PORT
      LAYER M5 ;
        RECT 200.976000 224.556000 201.000000 224.640000 ;
    END
  END i_lim[7]
  PIN i_lim[8]
    DIRECTION INPUT ;
    USE SIGNAL ;
    PORT
      LAYER M5 ;
        RECT 201.696000 224.556000 201.720000 224.640000 ;
    END
  END i_lim[8]
  PIN i_lim[9]
    DIRECTION INPUT ;
    USE SIGNAL ;
    PORT
      LAYER M5 ;
        RECT 202.416000 224.556000 202.440000 224.640000 ;
    END
  END i_lim[9]
  PIN i_v
    DIRECTION INPUT ;
    USE SIGNAL ;
    PORT
      LAYER M5 ;
        RECT 7.872000 224.556000 7.896000 224.640000 ;
    END
  END i_v
  PIN i_w[0]
    DIRECTION INPUT ;
    USE SIGNAL ;
    PORT
      LAYER M5 ;
        RECT 173.712000 224.556000 173.736000 224.640000 ;
    END
  END i_w[0]
  PIN i_w[10]
    DIRECTION INPUT ;
    USE SIGNAL ;
    PORT
      LAYER M5 ;
        RECT 180.672000 224.556000 180.696000 224.640000 ;
    END
  END i_w[10]
  PIN i_w[11]
    DIRECTION INPUT ;
    USE SIGNAL ;
    PORT
      LAYER M5 ;
        RECT 181.392000 224.556000 181.416000 224.640000 ;
    END
  END i_w[11]
  PIN i_w[12]
    DIRECTION INPUT ;
    USE SIGNAL ;
    PORT
      LAYER M5 ;
        RECT 182.064000 224.556000 182.088000 224.640000 ;
    END
  END i_w[12]
  PIN i_w[13]
    DIRECTION INPUT ;
    USE SIGNAL ;
    PORT
      LAYER M5 ;
        RECT 182.784000 224.556000 182.808000 224.640000 ;
    END
  END i_w[13]
  PIN i_w[14]
    DIRECTION INPUT ;
    USE SIGNAL ;
    PORT
      LAYER M5 ;
        RECT 183.504000 224.556000 183.528000 224.640000 ;
    END
  END i_w[14]
  PIN i_w[15]
    DIRECTION INPUT ;
    USE SIGNAL ;
    PORT
      LAYER M5 ;
        RECT 184.176000 224.556000 184.200000 224.640000 ;
    END
  END i_w[15]
  PIN i_w[16]
    DIRECTION INPUT ;
    USE SIGNAL ;
    PORT
      LAYER M5 ;
        RECT 184.896000 224.556000 184.920000 224.640000 ;
    END
  END i_w[16]
  PIN i_w[17]
    DIRECTION INPUT ;
    USE SIGNAL ;
    PORT
      LAYER M5 ;
        RECT 185.616000 224.556000 185.640000 224.640000 ;
    END
  END i_w[17]
  PIN i_w[18]
    DIRECTION INPUT ;
    USE SIGNAL ;
    PORT
      LAYER M5 ;
        RECT 186.288000 224.556000 186.312000 224.640000 ;
    END
  END i_w[18]
  PIN i_w[19]
    DIRECTION INPUT ;
    USE SIGNAL ;
    PORT
      LAYER M5 ;
        RECT 187.008000 224.556000 187.032000 224.640000 ;
    END
  END i_w[19]
  PIN i_w[1]
    DIRECTION INPUT ;
    USE SIGNAL ;
    PORT
      LAYER M5 ;
        RECT 174.384000 224.556000 174.408000 224.640000 ;
    END
  END i_w[1]
  PIN i_w[20]
    DIRECTION INPUT ;
    USE SIGNAL ;
    PORT
      LAYER M5 ;
        RECT 187.680000 224.556000 187.704000 224.640000 ;
    END
  END i_w[20]
  PIN i_w[21]
    DIRECTION INPUT ;
    USE SIGNAL ;
    PORT
      LAYER M5 ;
        RECT 188.400000 224.556000 188.424000 224.640000 ;
    END
  END i_w[21]
  PIN i_w[22]
    DIRECTION INPUT ;
    USE SIGNAL ;
    PORT
      LAYER M5 ;
        RECT 189.120000 224.556000 189.144000 224.640000 ;
    END
  END i_w[22]
  PIN i_w[23]
    DIRECTION INPUT ;
    USE SIGNAL ;
    PORT
      LAYER M5 ;
        RECT 189.792000 224.556000 189.816000 224.640000 ;
    END
  END i_w[23]
  PIN i_w[24]
    DIRECTION INPUT ;
    USE SIGNAL ;
    PORT
      LAYER M5 ;
        RECT 190.512000 224.556000 190.536000 224.640000 ;
    END
  END i_w[24]
  PIN i_w[25]
    DIRECTION INPUT ;
    USE SIGNAL ;
    PORT
      LAYER M5 ;
        RECT 191.184000 224.556000 191.208000 224.640000 ;
    END
  END i_w[25]
  PIN i_w[26]
    DIRECTION INPUT ;
    USE SIGNAL ;
    PORT
      LAYER M5 ;
        RECT 191.904000 224.556000 191.928000 224.640000 ;
    END
  END i_w[26]
  PIN i_w[27]
    DIRECTION INPUT ;
    USE SIGNAL ;
    PORT
      LAYER M5 ;
        RECT 192.576000 224.556000 192.600000 224.640000 ;
    END
  END i_w[27]
  PIN i_w[28]
    DIRECTION INPUT ;
    USE SIGNAL ;
    PORT
      LAYER M5 ;
        RECT 193.296000 224.556000 193.320000 224.640000 ;
    END
  END i_w[28]
  PIN i_w[29]
    DIRECTION INPUT ;
    USE SIGNAL ;
    PORT
      LAYER M5 ;
        RECT 194.016000 224.556000 194.040000 224.640000 ;
    END
  END i_w[29]
  PIN i_w[2]
    DIRECTION INPUT ;
    USE SIGNAL ;
    PORT
      LAYER M5 ;
        RECT 175.104000 224.556000 175.128000 224.640000 ;
    END
  END i_w[2]
  PIN i_w[30]
    DIRECTION INPUT ;
    USE SIGNAL ;
    PORT
      LAYER M5 ;
        RECT 194.688000 224.556000 194.712000 224.640000 ;
    END
  END i_w[30]
  PIN i_w[31]
    DIRECTION INPUT ;
    USE SIGNAL ;
    PORT
      LAYER M5 ;
        RECT 195.408000 224.556000 195.432000 224.640000 ;
    END
  END i_w[31]
  PIN i_w[3]
    DIRECTION INPUT ;
    USE SIGNAL ;
    PORT
      LAYER M5 ;
        RECT 175.776000 224.556000 175.800000 224.640000 ;
    END
  END i_w[3]
  PIN i_w[4]
    DIRECTION INPUT ;
    USE SIGNAL ;
    PORT
      LAYER M5 ;
        RECT 176.496000 224.556000 176.520000 224.640000 ;
    END
  END i_w[4]
  PIN i_w[5]
    DIRECTION INPUT ;
    USE SIGNAL ;
    PORT
      LAYER M5 ;
        RECT 177.216000 224.556000 177.240000 224.640000 ;
    END
  END i_w[5]
  PIN i_w[6]
    DIRECTION INPUT ;
    USE SIGNAL ;
    PORT
      LAYER M5 ;
        RECT 177.888000 224.556000 177.912000 224.640000 ;
    END
  END i_w[6]
  PIN i_w[7]
    DIRECTION INPUT ;
    USE SIGNAL ;
    PORT
      LAYER M5 ;
        RECT 178.608000 224.556000 178.632000 224.640000 ;
    END
  END i_w[7]
  PIN i_w[8]
    DIRECTION INPUT ;
    USE SIGNAL ;
    PORT
      LAYER M5 ;
        RECT 179.328000 224.556000 179.352000 224.640000 ;
    END
  END i_w[8]
  PIN i_w[9]
    DIRECTION INPUT ;
    USE SIGNAL ;
    PORT
      LAYER M5 ;
        RECT 180.000000 224.556000 180.024000 224.640000 ;
    END
  END i_w[9]
  PIN o_d[0]
    DIRECTION OUTPUT ;
    USE SIGNAL ;
    PORT
      LAYER M5 ;
        RECT 13.440000 0.000000 13.464000 0.084000 ;
    END
  END o_d[0]
  PIN o_d[10]
    DIRECTION OUTPUT ;
    USE SIGNAL ;
    PORT
      LAYER M5 ;
        RECT 44.736000 0.000000 44.760000 0.084000 ;
    END
  END o_d[10]
  PIN o_d[11]
    DIRECTION OUTPUT ;
    USE SIGNAL ;
    PORT
      LAYER M5 ;
        RECT 47.904000 0.000000 47.928000 0.084000 ;
    END
  END o_d[11]
  PIN o_d[12]
    DIRECTION OUTPUT ;
    USE SIGNAL ;
    PORT
      LAYER M5 ;
        RECT 50.976000 0.000000 51.000000 0.084000 ;
    END
  END o_d[12]
  PIN o_d[13]
    DIRECTION OUTPUT ;
    USE SIGNAL ;
    PORT
      LAYER M5 ;
        RECT 54.144000 0.000000 54.168000 0.084000 ;
    END
  END o_d[13]
  PIN o_d[14]
    DIRECTION OUTPUT ;
    USE SIGNAL ;
    PORT
      LAYER M5 ;
        RECT 57.312000 0.000000 57.336000 0.084000 ;
    END
  END o_d[14]
  PIN o_d[15]
    DIRECTION OUTPUT ;
    USE SIGNAL ;
    PORT
      LAYER M5 ;
        RECT 60.432000 0.000000 60.456000 0.084000 ;
    END
  END o_d[15]
  PIN o_d[16]
    DIRECTION OUTPUT ;
    USE SIGNAL ;
    PORT
      LAYER M5 ;
        RECT 63.600000 0.000000 63.624000 0.084000 ;
    END
  END o_d[16]
  PIN o_d[17]
    DIRECTION OUTPUT ;
    USE SIGNAL ;
    PORT
      LAYER M5 ;
        RECT 66.720000 0.000000 66.744000 0.084000 ;
    END
  END o_d[17]
  PIN o_d[18]
    DIRECTION OUTPUT ;
    USE SIGNAL ;
    PORT
      LAYER M5 ;
        RECT 69.888000 0.000000 69.912000 0.084000 ;
    END
  END o_d[18]
  PIN o_d[19]
    DIRECTION OUTPUT ;
    USE SIGNAL ;
    PORT
      LAYER M5 ;
        RECT 73.008000 0.000000 73.032000 0.084000 ;
    END
  END o_d[19]
  PIN o_d[1]
    DIRECTION OUTPUT ;
    USE SIGNAL ;
    PORT
      LAYER M5 ;
        RECT 16.464000 0.000000 16.488000 0.084000 ;
    END
  END o_d[1]
  PIN o_d[20]
    DIRECTION OUTPUT ;
    USE SIGNAL ;
    PORT
      LAYER M5 ;
        RECT 76.176000 0.000000 76.200000 0.084000 ;
    END
  END o_d[20]
  PIN o_d[21]
    DIRECTION OUTPUT ;
    USE SIGNAL ;
    PORT
      LAYER M5 ;
        RECT 79.296000 0.000000 79.320000 0.084000 ;
    END
  END o_d[21]
  PIN o_d[22]
    DIRECTION OUTPUT ;
    USE SIGNAL ;
    PORT
      LAYER M5 ;
        RECT 82.416000 0.000000 82.440000 0.084000 ;
    END
  END o_d[22]
  PIN o_d[23]
    DIRECTION OUTPUT ;
    USE SIGNAL ;
    PORT
      LAYER M5 ;
        RECT 85.584000 0.000000 85.608000 0.084000 ;
    END
  END o_d[23]
  PIN o_d[24]
    DIRECTION OUTPUT ;
    USE SIGNAL ;
    PORT
      LAYER M5 ;
        RECT 88.752000 0.000000 88.776000 0.084000 ;
    END
  END o_d[24]
  PIN o_d[25]
    DIRECTION OUTPUT ;
    USE SIGNAL ;
    PORT
      LAYER M5 ;
        RECT 91.872000 0.000000 91.896000 0.084000 ;
    END
  END o_d[25]
  PIN o_d[26]
    DIRECTION OUTPUT ;
    USE SIGNAL ;
    PORT
      LAYER M5 ;
        RECT 95.040000 0.000000 95.064000 0.084000 ;
    END
  END o_d[26]
  PIN o_d[27]
    DIRECTION OUTPUT ;
    USE SIGNAL ;
    PORT
      LAYER M5 ;
        RECT 98.160000 0.000000 98.184000 0.084000 ;
    END
  END o_d[27]
  PIN o_d[28]
    DIRECTION OUTPUT ;
    USE SIGNAL ;
    PORT
      LAYER M5 ;
        RECT 101.280000 0.000000 101.304000 0.084000 ;
    END
  END o_d[28]
  PIN o_d[29]
    DIRECTION OUTPUT ;
    USE SIGNAL ;
    PORT
      LAYER M5 ;
        RECT 104.448000 0.000000 104.472000 0.084000 ;
    END
  END o_d[29]
  PIN o_d[2]
    DIRECTION OUTPUT ;
    USE SIGNAL ;
    PORT
      LAYER M5 ;
        RECT 19.584000 0.000000 19.608000 0.084000 ;
    END
  END o_d[2]
  PIN o_d[30]
    DIRECTION OUTPUT ;
    USE SIGNAL ;
    PORT
      LAYER M5 ;
        RECT 107.616000 0.000000 107.640000 0.084000 ;
    END
  END o_d[30]
  PIN o_d[31]
    DIRECTION OUTPUT ;
    USE SIGNAL ;
    PORT
      LAYER M5 ;
        RECT 110.736000 0.000000 110.760000 0.084000 ;
    END
  END o_d[31]
  PIN o_d[32]
    DIRECTION OUTPUT ;
    USE SIGNAL ;
    PORT
      LAYER M5 ;
        RECT 113.856000 0.000000 113.880000 0.084000 ;
    END
  END o_d[32]
  PIN o_d[33]
    DIRECTION OUTPUT ;
    USE SIGNAL ;
    PORT
      LAYER M5 ;
        RECT 117.024000 0.000000 117.048000 0.084000 ;
    END
  END o_d[33]
  PIN o_d[34]
    DIRECTION OUTPUT ;
    USE SIGNAL ;
    PORT
      LAYER M5 ;
        RECT 120.144000 0.000000 120.168000 0.084000 ;
    END
  END o_d[34]
  PIN o_d[35]
    DIRECTION OUTPUT ;
    USE SIGNAL ;
    PORT
      LAYER M5 ;
        RECT 123.312000 0.000000 123.336000 0.084000 ;
    END
  END o_d[35]
  PIN o_d[36]
    DIRECTION OUTPUT ;
    USE SIGNAL ;
    PORT
      LAYER M5 ;
        RECT 126.480000 0.000000 126.504000 0.084000 ;
    END
  END o_d[36]
  PIN o_d[37]
    DIRECTION OUTPUT ;
    USE SIGNAL ;
    PORT
      LAYER M5 ;
        RECT 129.600000 0.000000 129.624000 0.084000 ;
    END
  END o_d[37]
  PIN o_d[38]
    DIRECTION OUTPUT ;
    USE SIGNAL ;
    PORT
      LAYER M5 ;
        RECT 132.720000 0.000000 132.744000 0.084000 ;
    END
  END o_d[38]
  PIN o_d[39]
    DIRECTION OUTPUT ;
    USE SIGNAL ;
    PORT
      LAYER M5 ;
        RECT 135.888000 0.000000 135.912000 0.084000 ;
    END
  END o_d[39]
  PIN o_d[3]
    DIRECTION OUTPUT ;
    USE SIGNAL ;
    PORT
      LAYER M5 ;
        RECT 22.752000 0.000000 22.776000 0.084000 ;
    END
  END o_d[3]
  PIN o_d[40]
    DIRECTION OUTPUT ;
    USE SIGNAL ;
    PORT
      LAYER M5 ;
        RECT 139.008000 0.000000 139.032000 0.084000 ;
    END
  END o_d[40]
  PIN o_d[41]
    DIRECTION OUTPUT ;
    USE SIGNAL ;
    PORT
      LAYER M5 ;
        RECT 142.176000 0.000000 142.200000 0.084000 ;
    END
  END o_d[41]
  PIN o_d[42]
    DIRECTION OUTPUT ;
    USE SIGNAL ;
    PORT
      LAYER M5 ;
        RECT 145.296000 0.000000 145.320000 0.084000 ;
    END
  END o_d[42]
  PIN o_d[43]
    DIRECTION OUTPUT ;
    USE SIGNAL ;
    PORT
      LAYER M5 ;
        RECT 148.464000 0.000000 148.488000 0.084000 ;
    END
  END o_d[43]
  PIN o_d[44]
    DIRECTION OUTPUT ;
    USE SIGNAL ;
    PORT
      LAYER M5 ;
        RECT 151.584000 0.000000 151.608000 0.084000 ;
    END
  END o_d[44]
  PIN o_d[45]
    DIRECTION OUTPUT ;
    USE SIGNAL ;
    PORT
      LAYER M5 ;
        RECT 154.752000 0.000000 154.776000 0.084000 ;
    END
  END o_d[45]
  PIN o_d[46]
    DIRECTION OUTPUT ;
    USE SIGNAL ;
    PORT
      LAYER M5 ;
        RECT 157.872000 0.000000 157.896000 0.084000 ;
    END
  END o_d[46]
  PIN o_d[47]
    DIRECTION OUTPUT ;
    USE SIGNAL ;
    PORT
      LAYER M5 ;
        RECT 161.040000 0.000000 161.064000 0.084000 ;
    END
  END o_d[47]
  PIN o_d[48]
    DIRECTION OUTPUT ;
    USE SIGNAL ;
    PORT
      LAYER M5 ;
        RECT 164.160000 0.000000 164.184000 0.084000 ;
    END
  END o_d[48]
  PIN o_d[49]
    DIRECTION OUTPUT ;
    USE SIGNAL ;
    PORT
      LAYER M5 ;
        RECT 167.328000 0.000000 167.352000 0.084000 ;
    END
  END o_d[49]
  PIN o_d[4]
    DIRECTION OUTPUT ;
    USE SIGNAL ;
    PORT
      LAYER M5 ;
        RECT 25.872000 0.000000 25.896000 0.084000 ;
    END
  END o_d[4]
  PIN o_d[50]
    DIRECTION OUTPUT ;
    USE SIGNAL ;
    PORT
      LAYER M5 ;
        RECT 170.448000 0.000000 170.472000 0.084000 ;
    END
  END o_d[50]
  PIN o_d[51]
    DIRECTION OUTPUT ;
    USE SIGNAL ;
    PORT
      LAYER M5 ;
        RECT 173.616000 0.000000 173.640000 0.084000 ;
    END
  END o_d[51]
  PIN o_d[52]
    DIRECTION OUTPUT ;
    USE SIGNAL ;
    PORT
      LAYER M5 ;
        RECT 176.736000 0.000000 176.760000 0.084000 ;
    END
  END o_d[52]
  PIN o_d[53]
    DIRECTION OUTPUT ;
    USE SIGNAL ;
    PORT
      LAYER M5 ;
        RECT 179.856000 0.000000 179.880000 0.084000 ;
    END
  END o_d[53]
  PIN o_d[54]
    DIRECTION OUTPUT ;
    USE SIGNAL ;
    PORT
      LAYER M5 ;
        RECT 183.024000 0.000000 183.048000 0.084000 ;
    END
  END o_d[54]
  PIN o_d[55]
    DIRECTION OUTPUT ;
    USE SIGNAL ;
    PORT
      LAYER M5 ;
        RECT 186.144000 0.000000 186.168000 0.084000 ;
    END
  END o_d[55]
  PIN o_d[56]
    DIRECTION OUTPUT ;
    USE SIGNAL ;
    PORT
      LAYER M5 ;
        RECT 189.312000 0.000000 189.336000 0.084000 ;
    END
  END o_d[56]
  PIN o_d[57]
    DIRECTION OUTPUT ;
    USE SIGNAL ;
    PORT
      LAYER M5 ;
        RECT 192.432000 0.000000 192.456000 0.084000 ;
    END
  END o_d[57]
  PIN o_d[58]
    DIRECTION OUTPUT ;
    USE SIGNAL ;
    PORT
      LAYER M5 ;
        RECT 195.600000 0.000000 195.624000 0.084000 ;
    END
  END o_d[58]
  PIN o_d[59]
    DIRECTION OUTPUT ;
    USE SIGNAL ;
    PORT
      LAYER M5 ;
        RECT 198.720000 0.000000 198.744000 0.084000 ;
    END
  END o_d[59]
  PIN o_d[5]
    DIRECTION OUTPUT ;
    USE SIGNAL ;
    PORT
      LAYER M5 ;
        RECT 29.040000 0.000000 29.064000 0.084000 ;
    END
  END o_d[5]
  PIN o_d[60]
    DIRECTION OUTPUT ;
    USE SIGNAL ;
    PORT
      LAYER M5 ;
        RECT 201.888000 0.000000 201.912000 0.084000 ;
    END
  END o_d[60]
  PIN o_d[61]
    DIRECTION OUTPUT ;
    USE SIGNAL ;
    PORT
      LAYER M5 ;
        RECT 205.008000 0.000000 205.032000 0.084000 ;
    END
  END o_d[61]
  PIN o_d[62]
    DIRECTION OUTPUT ;
    USE SIGNAL ;
    PORT
      LAYER M5 ;
        RECT 208.128000 0.000000 208.152000 0.084000 ;
    END
  END o_d[62]
  PIN o_d[63]
    DIRECTION OUTPUT ;
    USE SIGNAL ;
    PORT
      LAYER M5 ;
        RECT 211.296000 0.000000 211.320000 0.084000 ;
    END
  END o_d[63]
  PIN o_d[6]
    DIRECTION OUTPUT ;
    USE SIGNAL ;
    PORT
      LAYER M5 ;
        RECT 32.160000 0.000000 32.184000 0.084000 ;
    END
  END o_d[6]
  PIN o_d[7]
    DIRECTION OUTPUT ;
    USE SIGNAL ;
    PORT
      LAYER M5 ;
        RECT 35.328000 0.000000 35.352000 0.084000 ;
    END
  END o_d[7]
  PIN o_d[8]
    DIRECTION OUTPUT ;
    USE SIGNAL ;
    PORT
      LAYER M5 ;
        RECT 38.448000 0.000000 38.472000 0.084000 ;
    END
  END o_d[8]
  PIN o_d[9]
    DIRECTION OUTPUT ;
    USE SIGNAL ;
    PORT
      LAYER M5 ;
        RECT 41.616000 0.000000 41.640000 0.084000 ;
    END
  END o_d[9]
  PIN o_f
    DIRECTION OUTPUT ;
    USE SIGNAL ;
    PORT
      LAYER M5 ;
        RECT 215.520000 0.000000 215.544000 0.084000 ;
    END
  END o_f
  PIN o_v
    DIRECTION OUTPUT ;
    USE SIGNAL ;
    PORT
      LAYER M5 ;
        RECT 9.120000 0.000000 9.144000 0.084000 ;
    END
  END o_v
  PIN rst_n
    DIRECTION INPUT ;
    USE SIGNAL ;
    PORT
      LAYER M5 ;
        RECT 167.952000 0.000000 167.976000 0.084000 ;
    END
  END rst_n
  PIN VDD
    DIRECTION INOUT ;
    USE POWER ;
    PORT
      LAYER M5 ;
        RECT  218.592 2.151 218.712 222.489 ;
        RECT  213.192 2.151 213.312 222.489 ;
        RECT  207.792 2.151 207.912 222.489 ;
        RECT  202.392 2.151 202.512 222.489 ;
        RECT  196.992 2.151 197.112 222.489 ;
        RECT  191.592 2.151 191.712 222.489 ;
        RECT  186.192 2.151 186.312 222.489 ;
        RECT  180.792 2.151 180.912 222.489 ;
        RECT  175.392 2.151 175.512 222.489 ;
        RECT  169.992 2.151 170.112 222.489 ;
        RECT  164.592 2.151 164.712 222.489 ;
        RECT  159.192 2.151 159.312 222.489 ;
        RECT  153.792 2.151 153.912 222.489 ;
        RECT  148.392 2.151 148.512 222.489 ;
        RECT  142.992 2.151 143.112 222.489 ;
        RECT  137.592 2.151 137.712 222.489 ;
        RECT  132.192 2.151 132.312 222.489 ;
        RECT  126.792 2.151 126.912 222.489 ;
        RECT  121.392 2.151 121.512 222.489 ;
        RECT  115.992 2.151 116.112 222.489 ;
        RECT  110.592 2.151 110.712 222.489 ;
        RECT  105.192 2.151 105.312 222.489 ;
        RECT  99.792 2.151 99.912 222.489 ;
        RECT  94.392 2.151 94.512 222.489 ;
        RECT  88.992 2.151 89.112 222.489 ;
        RECT  83.592 2.151 83.712 222.489 ;
        RECT  78.192 2.151 78.312 222.489 ;
        RECT  72.792 2.151 72.912 222.489 ;
        RECT  67.392 2.151 67.512 222.489 ;
        RECT  61.992 2.151 62.112 222.489 ;
        RECT  56.592 2.151 56.712 222.489 ;
        RECT  51.192 2.151 51.312 222.489 ;
        RECT  45.792 2.151 45.912 222.489 ;
        RECT  40.392 2.151 40.512 222.489 ;
        RECT  34.992 2.151 35.112 222.489 ;
        RECT  29.592 2.151 29.712 222.489 ;
        RECT  24.192 2.151 24.312 222.489 ;
        RECT  18.792 2.151 18.912 222.489 ;
        RECT  13.392 2.151 13.512 222.489 ;
        RECT  7.992 2.151 8.112 222.489 ;
        RECT  2.592 2.151 2.712 222.489 ;
    END
  END VDD
  PIN VSS
    DIRECTION INOUT ;
    USE GROUND ;
    PORT
      LAYER M5 ;
        RECT  218.4 2.137 218.52 222.503 ;
        RECT  213 2.137 213.12 222.503 ;
        RECT  207.6 2.137 207.72 222.503 ;
        RECT  202.2 2.137 202.32 222.503 ;
        RECT  196.8 2.137 196.92 222.503 ;
        RECT  191.4 2.137 191.52 222.503 ;
        RECT  186 2.137 186.12 222.503 ;
        RECT  180.6 2.137 180.72 222.503 ;
        RECT  175.2 2.137 175.32 222.503 ;
        RECT  169.8 2.137 169.92 222.503 ;
        RECT  164.4 2.137 164.52 222.503 ;
        RECT  159 2.137 159.12 222.503 ;
        RECT  153.6 2.137 153.72 222.503 ;
        RECT  148.2 2.137 148.32 222.503 ;
        RECT  142.8 2.137 142.92 222.503 ;
        RECT  137.4 2.137 137.52 222.503 ;
        RECT  132 2.137 132.12 222.503 ;
        RECT  126.6 2.137 126.72 222.503 ;
        RECT  121.2 2.137 121.32 222.503 ;
        RECT  115.8 2.137 115.92 222.503 ;
        RECT  110.4 2.137 110.52 222.503 ;
        RECT  105 2.137 105.12 222.503 ;
        RECT  99.6 2.137 99.72 222.503 ;
        RECT  94.2 2.137 94.32 222.503 ;
        RECT  88.8 2.137 88.92 222.503 ;
        RECT  83.4 2.137 83.52 222.503 ;
        RECT  78 2.137 78.12 222.503 ;
        RECT  72.6 2.137 72.72 222.503 ;
        RECT  67.2 2.137 67.32 222.503 ;
        RECT  61.8 2.137 61.92 222.503 ;
        RECT  56.4 2.137 56.52 222.503 ;
        RECT  51 2.137 51.12 222.503 ;
        RECT  45.6 2.137 45.72 222.503 ;
        RECT  40.2 2.137 40.32 222.503 ;
        RECT  34.8 2.137 34.92 222.503 ;
        RECT  29.4 2.137 29.52 222.503 ;
        RECT  24 2.137 24.12 222.503 ;
        RECT  18.6 2.137 18.72 222.503 ;
        RECT  13.2 2.137 13.32 222.503 ;
        RECT  7.8 2.137 7.92 222.503 ;
        RECT  2.4 2.137 2.52 222.503 ;
    END
  END VSS
  OBS
    LAYER M1 ;
      RECT 0 0 224.640 224.640 ;
    LAYER M2 ;
      RECT 0 0 224.640 224.640 ;
    LAYER M3 ;
      RECT 0 0 224.640 224.640 ;
    LAYER M4 ;
      RECT 0 0 224.640 224.640 ;
    LAYER M5 ;
      RECT 0 0 224.640 224.640 ;
  END
END ot_s81sl_vsw
END LIBRARY
